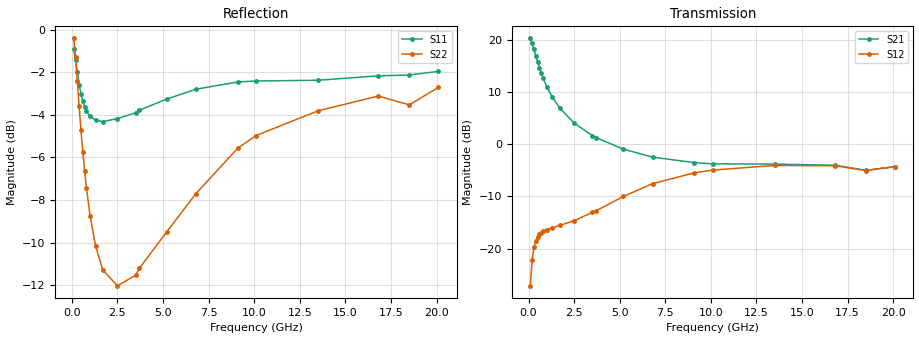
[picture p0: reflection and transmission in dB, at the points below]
!  Infineon Technologies AG
! BFR380L3 , PF131585-7, No.6, Th 09.10.01, soldered on pcb-board, measured with PP GSG850
!  Vce=0.5 V,  Ic=3.0 mA
! Common Emitter S-Parameters:  15. November 2001
#  GHz  S  MA  R  50
! f  S11  S21  S12  S22
! GHz  Mag  Ang  Mag  Ang  Mag  Ang  Mag  Ang
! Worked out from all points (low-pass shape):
!   201 points, 100 MHz to 20.1 GHz, reference 50 ohm
!   highest |S21| = 20.22 dB at 100 MHz (marker M1); lowest = -5.0 dB at 18.5 GHz (marker M2)
!   |S21| within 3 dB of the highest: start of sweep to 371.5 MHz
!   lowest |S11| = -4.3 dB at 1.7 GHz (marker M3), VSWR 4.10, Z = 12.2 - j2.49 ohm
!   |S11| at or under -10 dB: nowhere
!   |S22| runs from -12.0 to -0.4 dB; largest |S21 - S12| = 10
!   S11 on the Smith chart (normalised r, x): 100 MHz: 0.90, -3.91; 400 MHz: 0.29, -0.95; 1 GHz: 0.25, -0.29; 3.7 GHz: 0.23, +0.30; 9.1 GHz: 0.31, +1.07; 20.1 GHz: 0.95, +2.58
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0.1  0.8999 -27.4  10.26 161.9  0.04437 73.7  0.9536 -17.8
0.2  0.8478 -52.2  9.18 146.2  0.07894 61.8  0.8624 -33.5
0.3  0.7939 -73.3  8.031 133.7  0.1032 52.0  0.7561 -45.7
0.4  0.7426 -90.2  6.978 123.7  0.1192 44.9  0.6602 -55.4
0.5  0.7077 -104.0  6.085 115.6  0.13 40.0  0.5809 -63.1
0.6  0.6786 -115.4  5.352 109.2  0.1373 36.4  0.517 -69.3
0.7  0.6587 -124.8  4.766 103.6  0.1427 33.7  0.4658 -74.6
0.8  0.6437 -132.7  4.277 98.9  0.1467 32.0  0.4251 -79.0
1  0.6257 -145.6  3.551 91.1  0.1528 29.7  0.3656 -86.4
1.3  0.6134 -159.8  2.824 81.7  0.1589 28.7  0.3106 -95.5
1.7  0.6082 -173.9  2.225 71.4  0.1669 29.4  0.2724 -105.4
2.5  0.6182 166.2  1.592 55.2  0.1854 33.4  0.2506 -122.0
3.5  0.6381 147.4  1.207 39.2  0.2229 38.5  0.2651 -140.6
3.7  0.647 144.7  1.156 36.7  0.2302 38.7  0.2752 -144.5
5.2  0.6869 122.9  0.8959 19.7  0.3166 38.2  0.3351 -169.3
6.8  0.7243 103.7  0.7522 8.0  0.4189 31.2  0.412 164.8
9.1  0.7536 83.3  0.6653 -2.2  0.532 16.0  0.5269 136.3
10.1  0.7574 76.0  0.6484 -5.7  0.5652 9.3  0.564 125.1
13.5  0.7605 58.5  0.6449 -19.6  0.6259 -12.1  0.6447 95.0
16.8  0.7787 47.1  0.6286 -31.5  0.6215 -27.6  0.6982 74.0
18.5  0.7824 45.2  0.5626 -39.0  0.559 -35.7  0.6656 68.9
20.1  0.7977 38.2  0.609 -43.1  0.6103 -40.5  0.7316 58.5
